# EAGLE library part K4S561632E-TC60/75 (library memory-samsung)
CMOS SDRAM 256Mb, Samsung

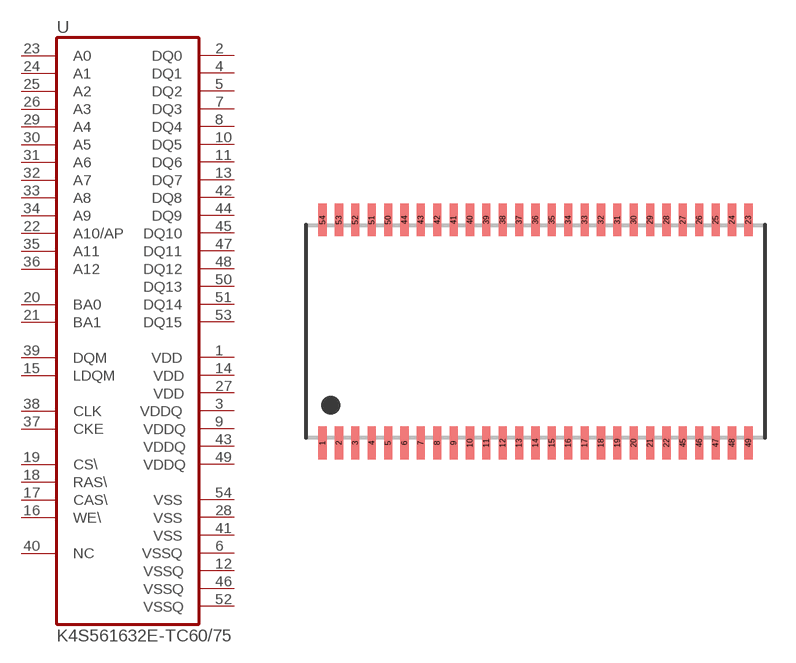
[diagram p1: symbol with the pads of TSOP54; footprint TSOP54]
Designator prefix U

## K4S561632E-TC60/75  [TSOP54]
1  VDD  pwr
2  DQ0
3  VDDQ  pwr
4  DQ1
5  DQ2
6  VSSQ  pwr
7  DQ3
8  DQ4
9  VDDQ  pwr
10  DQ5
11  DQ6
12  VSSQ  pwr
13  DQ7
14  VDD  pwr
15  LDQM  in
16  WE\  in
17  CAS\  in
18  RAS\  in
19  CS\  in
20  BA0  in
21  BA1  in
22  A10/AP  in
23  A0  in
24  A1  in
25  A2  in
26  A3  in
27  VDD  pwr
28  VSS  pwr
29  A4  in
30  A5  in
31  A6  in
32  A7  in
33  A8  in
34  A9  in
35  A11  in
36  A12  in
37  CKE  in
38  CLK  in
39  DQM  in
40  NC  nc
41  VSS  pwr
42  DQ8
43  VDDQ  pwr
44  DQ9
45  DQ10
46  VSSQ  pwr
47  DQ11
48  DQ12
49  VDDQ  pwr
50  DQ13
51  DQ14
52  VSSQ  pwr
53  DQ15
54  VSS  pwr

## Footprint TSOP54 (pad centres in mm)
TSOP 54 Pin, pitch 0.8 mm
smd 0.4 x 1.6: 1 -10.4,-5.45; 2 -9.6,-5.45; 3 -8.8,-5.45; 4 -8,-5.45; 5 -7.2,-5.45; 6 -6.4,-5.45; 7 -5.6,-5.45; 8 -4.8,-5.45; 9 -4,-5.45; 10 -3.2,-5.45; 11 -2.4,-5.45; 12 -1.6,-5.45; 13 -0.8,-5.45; 14 0,-5.45; 15 0.8,-5.45; 16 1.6,-5.45; 17 2.4,-5.45; 18 3.2,-5.45; 19 4,-5.45; 20 4.8,-5.45; 21 5.6,-5.45; 22 6.4,-5.45; 23 10.4,5.45; 24 9.6,5.45; 25 8.8,5.45; 26 8,5.45; 27 7.2,5.45; 28 6.4,5.45; 29 5.6,5.45; 30 4.8,5.45; 31 4,5.45; 32 3.2,5.45; 33 2.4,5.45; 34 1.6,5.45; 35 0.8,5.45; 36 0,5.45; 37 -0.8,5.45; 38 -1.6,5.45; 39 -2.4,5.45; 40 -3.2,5.45; 41 -4,5.45; 42 -4.8,5.45; 43 -5.6,5.45; 44 -6.4,5.45; 45 7.2,-5.45; 46 8,-5.45; 47 8.8,-5.45; 48 9.6,-5.45; 49 10.4,-5.45; 50 -7.2,5.45; 51 -8,5.45; 52 -8.8,5.45; 53 -9.6,5.45; 54 -10.4,5.45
